VERSION 5.7 ;
  NOWIREEXTENSIONATPIN ON ;
  DIVIDERCHAR "/" ;
  BUSBITCHARS "[]" ;
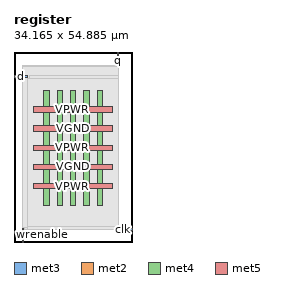
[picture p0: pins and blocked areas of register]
MACRO register
  CLASS BLOCK ;
  FOREIGN register ;
  ORIGIN 0.000 0.000 ;
  SIZE 34.165 BY 54.885 ;
  PIN clk
    DIRECTION INPUT ;
    USE SIGNAL ;
    PORT
      LAYER met3 ;
        RECT 30.165 3.440 34.165 4.040 ;
    END
  END clk
  PIN d
    DIRECTION INPUT ;
    USE SIGNAL ;
    PORT
      LAYER met3 ;
        RECT 0.000 47.640 4.000 48.240 ;
    END
  END d
  PIN q
    DIRECTION OUTPUT TRISTATE ;
    USE SIGNAL ;
    PORT
      LAYER met2 ;
        RECT 29.990 50.885 30.270 54.885 ;
    END
  END q
  PIN wrenable
    DIRECTION INPUT ;
    USE SIGNAL ;
    PORT
      LAYER met2 ;
        RECT 2.390 0.000 2.670 4.000 ;
    END
  END wrenable
  PIN VPWR
    DIRECTION INOUT ;
    USE POWER ;
    PORT
      LAYER met4 ;
        RECT 23.990 10.640 25.590 43.760 ;
    END
  END VPWR
  PIN VPWR
    DIRECTION INOUT ;
    USE POWER ;
    PORT
      LAYER met4 ;
        RECT 16.280 10.640 17.880 43.760 ;
    END
  END VPWR
  PIN VPWR
    DIRECTION INOUT ;
    USE POWER ;
    PORT
      LAYER met4 ;
        RECT 8.575 10.640 10.175 43.760 ;
    END
  END VPWR
  PIN VPWR
    DIRECTION INOUT ;
    USE POWER ;
    PORT
      LAYER met5 ;
        RECT 5.520 37.445 28.520 39.045 ;
    END
  END VPWR
  PIN VPWR
    DIRECTION INOUT ;
    USE POWER ;
    PORT
      LAYER met5 ;
        RECT 5.520 26.405 28.520 28.005 ;
    END
  END VPWR
  PIN VPWR
    DIRECTION INOUT ;
    USE POWER ;
    PORT
      LAYER met5 ;
        RECT 5.520 15.360 28.520 16.960 ;
    END
  END VPWR
  PIN VGND
    DIRECTION INOUT ;
    USE GROUND ;
    PORT
      LAYER met4 ;
        RECT 20.135 10.640 21.735 43.760 ;
    END
  END VGND
  PIN VGND
    DIRECTION INOUT ;
    USE GROUND ;
    PORT
      LAYER met4 ;
        RECT 12.430 10.640 14.030 43.760 ;
    END
  END VGND
  PIN VGND
    DIRECTION INOUT ;
    USE GROUND ;
    PORT
      LAYER met5 ;
        RECT 5.520 31.925 28.520 33.525 ;
    END
  END VGND
  PIN VGND
    DIRECTION INOUT ;
    USE GROUND ;
    PORT
      LAYER met5 ;
        RECT 5.520 20.880 28.520 22.480 ;
    END
  END VGND
  OBS
      LAYER li1 ;
        RECT 5.520 10.795 28.520 43.605 ;
      LAYER met1 ;
        RECT 2.370 10.640 30.290 43.760 ;
      LAYER met2 ;
        RECT 2.400 50.605 29.710 50.885 ;
        RECT 2.400 4.280 30.260 50.605 ;
        RECT 2.950 3.555 30.260 4.280 ;
      LAYER met3 ;
        RECT 4.400 47.240 30.165 48.105 ;
        RECT 4.000 4.440 30.165 47.240 ;
        RECT 4.000 3.575 29.765 4.440 ;
  END
END register
END LIBRARY

